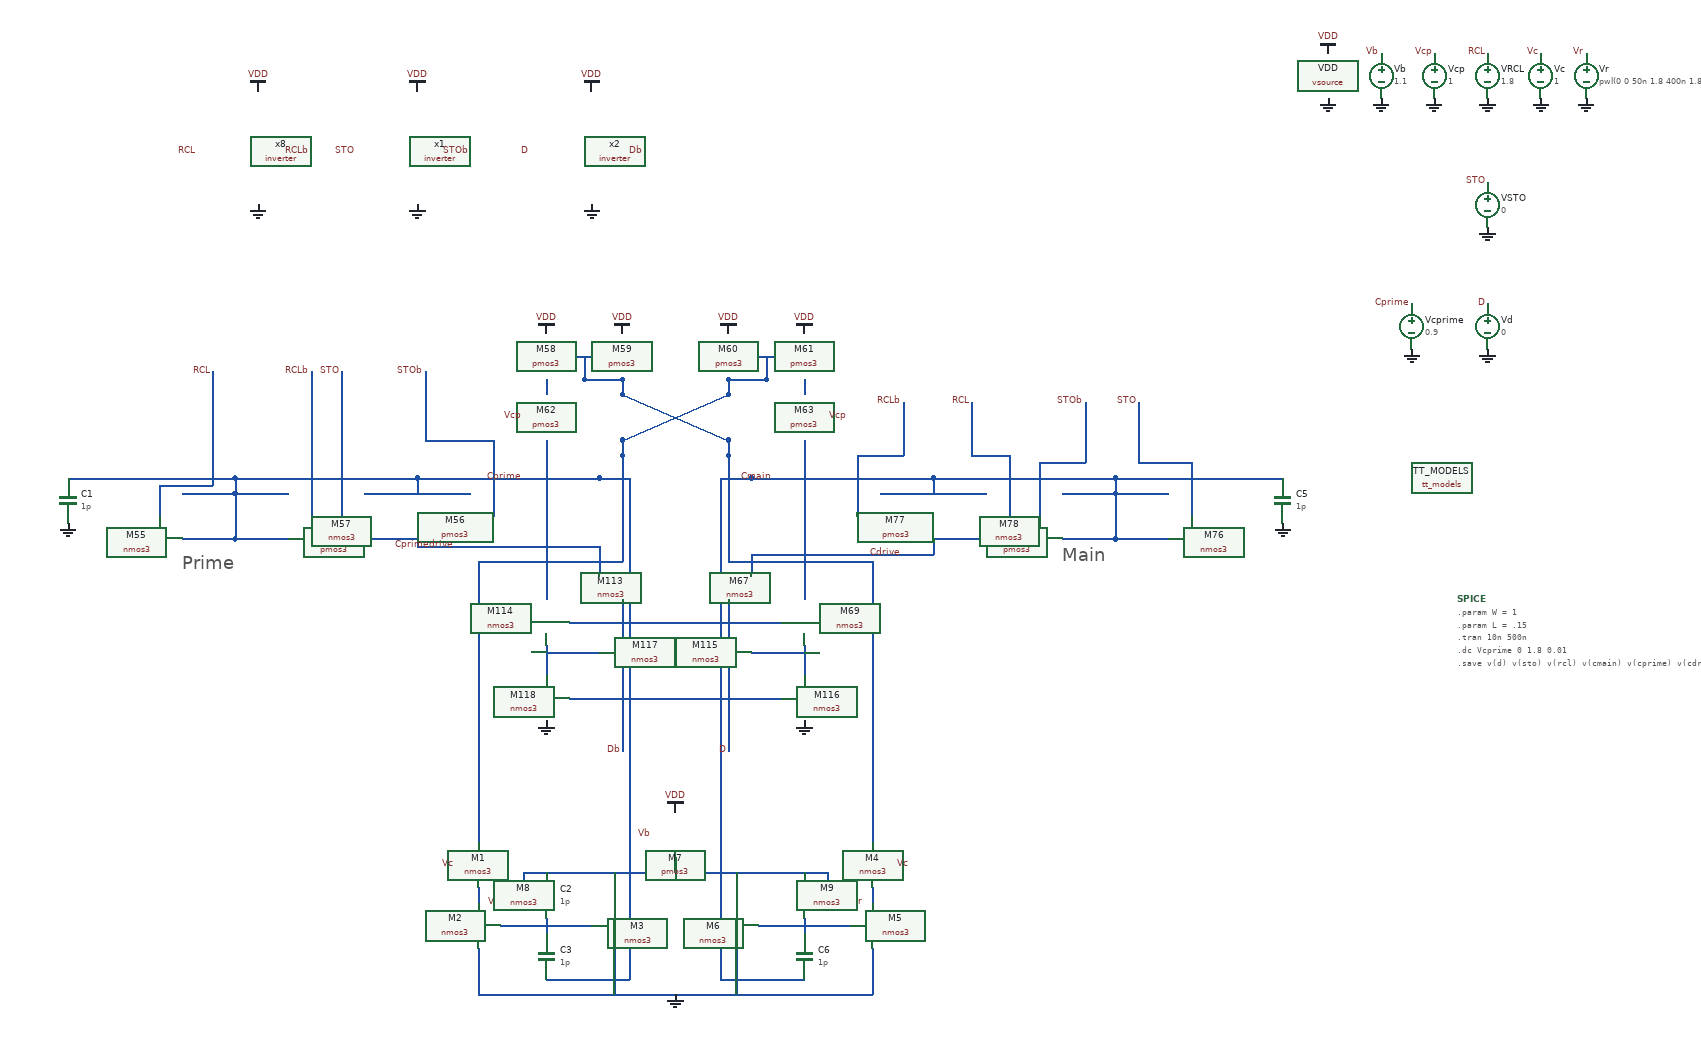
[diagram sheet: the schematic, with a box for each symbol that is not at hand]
v {xschem version=3.4.3 file_version=1.2
}
G {}
K {}
V {}
S {}
E {}
T {Prime} -550 -80 0 0 0.7 0.7 {}
T {Main} 610 -90 0 0 0.7 0.7 {}
N -550 -160 -410 -160 {
lab=Cprime}
N -480 -180 -480 -160 {
lab=Cprime}
N -310 -160 -170 -160 {
lab=Cprime}
N -480 -180 -240 -180 {
lab=Cprime}
N -240 -180 -240 -160 {
lab=Cprime}
N -310 -100 -170 -100 {
lab=Cprimedrive}
N -40 -340 0 -340 {
lab=#net1}
N -20 -340 -20 -310 {
lab=#net1}
N -20 -310 30 -310 {
lab=#net1}
N 200 -340 240 -340 {
lab=#net2}
N 220 -340 220 -310 {
lab=#net2}
N 170 -310 220 -310 {
lab=#net2}
N 30 -310 30 -290 {
lab=#net1}
N 170 -230 170 -210 {
lab=#net1}
N 170 -310 170 -290 {
lab=#net2}
N 30 -230 30 -210 {
lab=#net2}
N 30 -230 170 -290 {
lab=#net2}
N 30 -290 170 -230 {
lab=#net1}
N 270 -310 270 -290 {
lab=#net3}
N -70 -310 -70 -290 {
lab=#net4}
N -240 -180 0 -180 {
lab=Cprime}
N -70 -230 -70 -20 {
lab=Cprimedrive}
N 270 -230 270 -20 {
lab=Cdrive}
N 610 -160 750 -160 {
lab=Cmain}
N 680 -180 680 -160 {
lab=Cmain}
N 370 -160 510 -160 {
lab=Cmain}
N 440 -180 680 -180 {
lab=Cmain}
N 440 -180 440 -160 {
lab=Cmain}
N 370 -100 510 -100 {
lab=Cdrive}
N 200 -180 440 -180 {
lab=Cmain}
N -550 -160 -410 -160 {
lab=Cprime}
N -480 -180 -480 -160 {
lab=Cprime}
N -310 -160 -170 -160 {
lab=Cprime}
N -480 -180 -240 -180 {
lab=Cprime}
N -240 -180 -240 -160 {
lab=Cprime}
N -310 -100 -170 -100 {
lab=Cprimedrive}
N -40 -340 0 -340 {
lab=#net1}
N -20 -340 -20 -310 {
lab=#net1}
N -20 -310 30 -310 {
lab=#net1}
N 200 -340 240 -340 {
lab=#net2}
N 220 -340 220 -310 {
lab=#net2}
N 170 -310 220 -310 {
lab=#net2}
N 30 -310 30 -290 {
lab=#net1}
N 170 -230 170 -210 {
lab=#net1}
N 170 -310 170 -290 {
lab=#net2}
N 30 -230 30 -210 {
lab=#net2}
N 30 -230 170 -290 {
lab=#net2}
N 30 -290 170 -230 {
lab=#net1}
N 270 -310 270 -290 {
lab=#net3}
N -70 -310 -70 -290 {
lab=#net4}
N -240 -180 0 -180 {
lab=Cprime}
N -70 -230 -70 -20 {
lab=Cprimedrive}
N 270 -230 270 -20 {
lab=Cdrive}
N 610 -160 750 -160 {
lab=Cmain}
N 680 -180 680 -160 {
lab=Cmain}
N 370 -160 510 -160 {
lab=Cmain}
N 440 -180 680 -180 {
lab=Cmain}
N 440 -180 440 -160 {
lab=Cmain}
N 370 -100 510 -100 {
lab=Cdrive}
N 200 -180 440 -180 {
lab=Cmain}
N -480 -160 -480 -100 {
lab=Cprime}
N -480 -100 -410 -100 {
lab=Cprime}
N -550 -100 -480 -100 {
lab=Cprime}
N -580 -170 -580 -130 {
lab=RCL}
N -580 -170 -510 -170 {
lab=RCL}
N -510 -320 -510 -170 {
lab=RCL}
N -380 -320 -380 -130 {
lab=RCLb}
N -340 -320 -340 -130 {
lab=STO}
N -140 -230 -140 -130 {
lab=STOb}
N -230 -230 -140 -230 {
lab=STOb}
N -230 -320 -230 -230 {
lab=STOb}
N -240 -100 -240 -90 {
lab=Cprimedrive}
N 0 -90 0 -50 {
lab=Cprimedrive}
N 680 -160 680 -100 {
lab=Cmain}
N 610 -100 680 -100 {
lab=Cmain}
N 680 -100 750 -100 {
lab=Cmain}
N 640 -280 640 -200 {
lab=STOb}
N 580 -200 640 -200 {
lab=STOb}
N 580 -200 580 -130 {
lab=STOb}
N 710 -280 710 -200 {
lab=STO}
N 710 -200 780 -200 {
lab=STO}
N 780 -200 780 -130 {
lab=STO}
N 400 -280 400 -210 {
lab=RCLb}
N 340 -210 400 -210 {
lab=RCLb}
N 340 -210 340 -130 {
lab=RCLb}
N 200 -80 200 -50 {
lab=Cdrive}
N 440 -100 440 -80 {
lab=Cdrive}
N 490 -280 490 -210 {
lab=RCL}
N 490 -210 540 -210 {
lab=RCL}
N 540 -210 540 -130 {
lab=RCL}
N -240 -90 -70 -90 {
lab=Cprimedrive}
N -70 -90 0 -90 {
lab=Cprimedrive}
N 200 -80 270 -80 {
lab=Cdrive}
N 270 -80 440 -80 {
lab=Cdrive}
N -40 10 240 10 {
lab=#net5}
N 270 40 270 80 {
lab=#net6}
N 200 50 270 50 {
lab=#net6}
N -70 40 -70 80 {
lab=#net7}
N -70 50 0 50 {
lab=#net7}
N 30 -20 30 180 {
lab=Db}
N 170 -20 170 180 {
lab=D}
N -40 110 240 110 {
lab=#net8}
N 680 -180 900 -180 {
lab=Cmain}
N -700 -180 -480 -180 {
lab=Cprime}
N -160 360 -160 380 {
lab=#net9}
N -130 410 -10 410 {
lab=#net10}
N -70 410 -70 420 {
lab=#net10}
N -70 400 -70 410 {
lab=#net10}
N 210 410 330 410 {
lab=#net11}
N 270 400 270 410 {
lab=#net11}
N 270 410 270 420 {
lab=#net11}
N -160 440 -160 500 {
lab=GND}
N -160 500 360 500 {
lab=GND}
N 360 440 360 500 {
lab=GND}
N 20 440 20 500 {
lab=GND}
N 180 440 180 500 {
lab=GND}
N -70 340 270 340 {
lab=#net12}
N 180 340 180 380 {
lab=#net12}
N 20 340 20 380 {
lab=#net12}
N 100 320 100 340 {
lab=#net12}
N 360 360 360 380 {
lab=#net13}
N 0 -180 40 -180 {
lab=Cprime}
N 40 -180 40 480 {
lab=Cprime}
N -70 480 40 480 {
lab=Cprime}
N 160 -180 200 -180 {
lab=Cmain}
N 160 -180 160 480 {
lab=Cmain}
N 160 480 270 480 {
lab=Cmain}
N -160 -70 -160 300 {
lab=#net2}
N -160 -70 30 -70 {
lab=#net2}
N 30 -210 30 -70 {
lab=#net2}
N 360 -70 360 300 {
lab=#net1}
N 170 -70 360 -70 {
lab=#net1}
N 170 -210 170 -70 {
lab=#net1}
N -100 340 -100 350 {
lab=#net12}
N -100 340 -70 340 {
lab=#net12}
N 300 340 300 350 {
lab=#net12}
N 270 340 300 340 {
lab=#net12}
C {madvlsi/pmos3.sym} -410 -130 0 1 {name=M54
L=\{L\}
W=\{W\}
body=VDD
nf=1
mult=1
ad="'int((nf+1)/2) * W/nf * 0.29'" 
pd="'2*int((nf+1)/2) * (W/nf + 0.29)'"
as="'int((nf+2)/2) * W/nf * 0.29'" 
ps="'2*int((nf+2)/2) * (W/nf + 0.29)'"
nrd="'0.29 / W'" nrs="'0.29 / W'"
sa=0 sb=0 sd=0
model=pfet_01v8
spiceprefix=X
}
C {madvlsi/nmos3.sym} -550 -130 2 1 {name=M55
L=\{L\}
W=\{W\}
body=GND
nf=1
mult=1
ad="'int((nf+1)/2) * W/nf * 0.29'" 
pd="'2*int((nf+1)/2) * (W/nf + 0.29)'"
as="'int((nf+2)/2) * W/nf * 0.29'" 
ps="'2*int((nf+2)/2) * (W/nf + 0.29)'"
nrd="'0.29 / W'" nrs="'0.29 / W'"
sa=0 sb=0 sd=0
model=nfet_01v8
spiceprefix=X
}
C {madvlsi/pmos3.sym} -170 -130 0 1 {name=M56
L=\{L\}
W=\{W\}
body=VDD
nf=1
mult=1
ad="'int((nf+1)/2) * W/nf * 0.29'" 
pd="'2*int((nf+1)/2) * (W/nf + 0.29)'"
as="'int((nf+2)/2) * W/nf * 0.29'" 
ps="'2*int((nf+2)/2) * (W/nf + 0.29)'"
nrd="'0.29 / W'" nrs="'0.29 / W'"
sa=0 sb=0 sd=0
model=pfet_01v8
spiceprefix=X
}
C {madvlsi/nmos3.sym} -310 -130 2 1 {name=M57
L=\{L\}
W=\{W\}
body=GND
nf=1
mult=1
ad="'int((nf+1)/2) * W/nf * 0.29'" 
pd="'2*int((nf+1)/2) * (W/nf + 0.29)'"
as="'int((nf+2)/2) * W/nf * 0.29'" 
ps="'2*int((nf+2)/2) * (W/nf + 0.29)'"
nrd="'0.29 / W'" nrs="'0.29 / W'"
sa=0 sb=0 sd=0
model=nfet_01v8
spiceprefix=X
}
C {madvlsi/pmos3.sym} -70 -340 0 1 {name=M58
L=\{L\}
W=\{W\}
body=VDD
nf=1
mult=1
ad="'int((nf+1)/2) * W/nf * 0.29'" 
pd="'2*int((nf+1)/2) * (W/nf + 0.29)'"
as="'int((nf+2)/2) * W/nf * 0.29'" 
ps="'2*int((nf+2)/2) * (W/nf + 0.29)'"
nrd="'0.29 / W'" nrs="'0.29 / W'"
sa=0 sb=0 sd=0
model=pfet_01v8
spiceprefix=X
}
C {madvlsi/pmos3.sym} 30 -340 0 0 {name=M59
L=\{L\}
W=\{W\}
body=VDD
nf=1
mult=1
ad="'int((nf+1)/2) * W/nf * 0.29'" 
pd="'2*int((nf+1)/2) * (W/nf + 0.29)'"
as="'int((nf+2)/2) * W/nf * 0.29'" 
ps="'2*int((nf+2)/2) * (W/nf + 0.29)'"
nrd="'0.29 / W'" nrs="'0.29 / W'"
sa=0 sb=0 sd=0
model=pfet_01v8
spiceprefix=X
}
C {madvlsi/pmos3.sym} 170 -340 0 1 {name=M60
L=\{L\}
W=\{W\}
body=VDD
nf=1
mult=1
ad="'int((nf+1)/2) * W/nf * 0.29'" 
pd="'2*int((nf+1)/2) * (W/nf + 0.29)'"
as="'int((nf+2)/2) * W/nf * 0.29'" 
ps="'2*int((nf+2)/2) * (W/nf + 0.29)'"
nrd="'0.29 / W'" nrs="'0.29 / W'"
sa=0 sb=0 sd=0
model=pfet_01v8
spiceprefix=X
}
C {madvlsi/pmos3.sym} 270 -340 0 0 {name=M61
L=\{L\}
W=\{W\}
body=VDD
nf=1
mult=1
ad="'int((nf+1)/2) * W/nf * 0.29'" 
pd="'2*int((nf+1)/2) * (W/nf + 0.29)'"
as="'int((nf+2)/2) * W/nf * 0.29'" 
ps="'2*int((nf+2)/2) * (W/nf + 0.29)'"
nrd="'0.29 / W'" nrs="'0.29 / W'"
sa=0 sb=0 sd=0
model=pfet_01v8
spiceprefix=X
}
C {madvlsi/pmos3.sym} -70 -260 0 0 {name=M62
L=\{L\}
W=\{W\}
body=VDD
nf=1
mult=1
ad="'int((nf+1)/2) * W/nf * 0.29'" 
pd="'2*int((nf+1)/2) * (W/nf + 0.29)'"
as="'int((nf+2)/2) * W/nf * 0.29'" 
ps="'2*int((nf+2)/2) * (W/nf + 0.29)'"
nrd="'0.29 / W'" nrs="'0.29 / W'"
sa=0 sb=0 sd=0
model=pfet_01v8
spiceprefix=X
}
C {madvlsi/pmos3.sym} 270 -260 0 1 {name=M63
L=\{L\}
W=\{W\}
body=VDD
nf=1
mult=1
ad="'int((nf+1)/2) * W/nf * 0.29'" 
pd="'2*int((nf+1)/2) * (W/nf + 0.29)'"
as="'int((nf+2)/2) * W/nf * 0.29'" 
ps="'2*int((nf+2)/2) * (W/nf + 0.29)'"
nrd="'0.29 / W'" nrs="'0.29 / W'"
sa=0 sb=0 sd=0
model=pfet_01v8
spiceprefix=X
}
C {madvlsi/pmos3.sym} 610 -130 0 0 {name=M75
L=\{L\}
W=\{W\}
body=VDD
nf=1
mult=1
ad="'int((nf+1)/2) * W/nf * 0.29'" 
pd="'2*int((nf+1)/2) * (W/nf + 0.29)'"
as="'int((nf+2)/2) * W/nf * 0.29'" 
ps="'2*int((nf+2)/2) * (W/nf + 0.29)'"
nrd="'0.29 / W'" nrs="'0.29 / W'"
sa=0 sb=0 sd=0
model=pfet_01v8
spiceprefix=X
}
C {madvlsi/nmos3.sym} 750 -130 2 0 {name=M76
L=\{L\}
W=\{W\}
body=GND
nf=1
mult=1
ad="'int((nf+1)/2) * W/nf * 0.29'" 
pd="'2*int((nf+1)/2) * (W/nf + 0.29)'"
as="'int((nf+2)/2) * W/nf * 0.29'" 
ps="'2*int((nf+2)/2) * (W/nf + 0.29)'"
nrd="'0.29 / W'" nrs="'0.29 / W'"
sa=0 sb=0 sd=0
model=nfet_01v8
spiceprefix=X
}
C {madvlsi/pmos3.sym} 370 -130 0 0 {name=M77
L=\{L\}
W=\{W\}
body=VDD
nf=1
mult=1
ad="'int((nf+1)/2) * W/nf * 0.29'" 
pd="'2*int((nf+1)/2) * (W/nf + 0.29)'"
as="'int((nf+2)/2) * W/nf * 0.29'" 
ps="'2*int((nf+2)/2) * (W/nf + 0.29)'"
nrd="'0.29 / W'" nrs="'0.29 / W'"
sa=0 sb=0 sd=0
model=pfet_01v8
spiceprefix=X
}
C {madvlsi/nmos3.sym} 510 -130 2 0 {name=M78
L=\{L\}
W=\{W\}
body=GND
nf=1
mult=1
ad="'int((nf+1)/2) * W/nf * 0.29'" 
pd="'2*int((nf+1)/2) * (W/nf + 0.29)'"
as="'int((nf+2)/2) * W/nf * 0.29'" 
ps="'2*int((nf+2)/2) * (W/nf + 0.29)'"
nrd="'0.29 / W'" nrs="'0.29 / W'"
sa=0 sb=0 sd=0
model=nfet_01v8
spiceprefix=X
}
C {devices/lab_pin.sym} -100 -260 0 0 {name=p78 sig_type=std_logic lab=Vcp}
C {devices/lab_pin.sym} 640 -280 1 0 {name=p91 sig_type=std_logic lab=STOb}
C {devices/lab_pin.sym} -230 -320 1 0 {name=p48 sig_type=std_logic lab=STOb}
C {devices/lab_pin.sym} 400 -280 1 0 {name=p70 sig_type=std_logic lab=RCLb}
C {devices/lab_pin.sym} -380 -320 1 0 {name=p46 sig_type=std_logic lab=RCLb}
C {devices/lab_pin.sym} -340 -320 1 0 {name=p29 sig_type=std_logic lab=STO}
C {devices/lab_pin.sym} 710 -280 1 0 {name=p30 sig_type=std_logic lab=STO}
C {devices/lab_pin.sym} -510 -320 1 0 {name=p45 sig_type=std_logic lab=RCL}
C {devices/lab_pin.sym} 490 -280 1 0 {name=p53 sig_type=std_logic lab=RCL}
C {devices/lab_pin.sym} -100 -180 3 0 {name=p59 sig_type=std_logic lab=Cprime}
C {devices/lab_pin.sym} 300 -260 2 0 {name=p8 sig_type=std_logic lab=Vcp}
C {madvlsi/vdd.sym} -70 -370 0 0 {name=l54 lab=VDD}
C {madvlsi/vdd.sym} 30 -370 0 0 {name=l55 lab=VDD}
C {madvlsi/vdd.sym} 170 -370 0 0 {name=l56 lab=VDD}
C {madvlsi/vdd.sym} 270 -370 0 0 {name=l57 lab=VDD}
C {devices/lab_pin.sym} -190 -90 3 0 {name=p2 sig_type=std_logic lab=Cprimedrive}
C {devices/lab_pin.sym} 400 -80 3 0 {name=p11 sig_type=std_logic lab=Cdrive}
C {madvlsi/nmos3.sym} 200 -20 0 0 {name=M67
L=\{L\}
W=\{W\}
body=GND
nf=1
mult=1
ad="'int((nf+1)/2) * W/nf * 0.29'" 
pd="'2*int((nf+1)/2) * (W/nf + 0.29)'"
as="'int((nf+2)/2) * W/nf * 0.29'" 
ps="'2*int((nf+2)/2) * (W/nf + 0.29)'"
nrd="'0.29 / W'" nrs="'0.29 / W'"
sa=0 sb=0 sd=0
model=nfet_01v8
spiceprefix=X
}
C {madvlsi/nmos3.sym} 270 10 0 0 {name=M69
L=\{L\}
W=\{W\}
body=GND
nf=1
mult=1
ad="'int((nf+1)/2) * W/nf * 0.29'" 
pd="'2*int((nf+1)/2) * (W/nf + 0.29)'"
as="'int((nf+2)/2) * W/nf * 0.29'" 
ps="'2*int((nf+2)/2) * (W/nf + 0.29)'"
nrd="'0.29 / W'" nrs="'0.29 / W'"
sa=0 sb=0 sd=0
model=nfet_01v8
spiceprefix=X
}
C {madvlsi/nmos3.sym} 0 -20 0 1 {name=M113
L=\{L\}
W=\{W\}
body=GND
nf=1
mult=1
ad="'int((nf+1)/2) * W/nf * 0.29'" 
pd="'2*int((nf+1)/2) * (W/nf + 0.29)'"
as="'int((nf+2)/2) * W/nf * 0.29'" 
ps="'2*int((nf+2)/2) * (W/nf + 0.29)'"
nrd="'0.29 / W'" nrs="'0.29 / W'"
sa=0 sb=0 sd=0
model=nfet_01v8
spiceprefix=X
}
C {madvlsi/nmos3.sym} -70 10 0 1 {name=M114
L=\{L\}
W=\{W\}
body=GND
nf=1
mult=1
ad="'int((nf+1)/2) * W/nf * 0.29'" 
pd="'2*int((nf+1)/2) * (W/nf + 0.29)'"
as="'int((nf+2)/2) * W/nf * 0.29'" 
ps="'2*int((nf+2)/2) * (W/nf + 0.29)'"
nrd="'0.29 / W'" nrs="'0.29 / W'"
sa=0 sb=0 sd=0
model=nfet_01v8
spiceprefix=X
}
C {madvlsi/nmos3.sym} 200 80 0 0 {name=M115
L=\{L\}
W=\{W\}
body=GND
nf=1
mult=1
ad="'int((nf+1)/2) * W/nf * 0.29'" 
pd="'2*int((nf+1)/2) * (W/nf + 0.29)'"
as="'int((nf+2)/2) * W/nf * 0.29'" 
ps="'2*int((nf+2)/2) * (W/nf + 0.29)'"
nrd="'0.29 / W'" nrs="'0.29 / W'"
sa=0 sb=0 sd=0
model=nfet_01v8
spiceprefix=X
}
C {madvlsi/nmos3.sym} 270 110 0 0 {name=M116
L=\{L\}
W=\{W\}
body=GND
nf=1
mult=1
ad="'int((nf+1)/2) * W/nf * 0.29'" 
pd="'2*int((nf+1)/2) * (W/nf + 0.29)'"
as="'int((nf+2)/2) * W/nf * 0.29'" 
ps="'2*int((nf+2)/2) * (W/nf + 0.29)'"
nrd="'0.29 / W'" nrs="'0.29 / W'"
sa=0 sb=0 sd=0
model=nfet_01v8
spiceprefix=X
}
C {madvlsi/nmos3.sym} 0 80 0 1 {name=M117
L=\{L\}
W=\{W\}
body=GND
nf=1
mult=1
ad="'int((nf+1)/2) * W/nf * 0.29'" 
pd="'2*int((nf+1)/2) * (W/nf + 0.29)'"
as="'int((nf+2)/2) * W/nf * 0.29'" 
ps="'2*int((nf+2)/2) * (W/nf + 0.29)'"
nrd="'0.29 / W'" nrs="'0.29 / W'"
sa=0 sb=0 sd=0
model=nfet_01v8
spiceprefix=X
}
C {madvlsi/nmos3.sym} -70 110 0 1 {name=M118
L=\{L\}
W=\{W\}
body=GND
nf=1
mult=1
ad="'int((nf+1)/2) * W/nf * 0.29'" 
pd="'2*int((nf+1)/2) * (W/nf + 0.29)'"
as="'int((nf+2)/2) * W/nf * 0.29'" 
ps="'2*int((nf+2)/2) * (W/nf + 0.29)'"
nrd="'0.29 / W'" nrs="'0.29 / W'"
sa=0 sb=0 sd=0
model=nfet_01v8
spiceprefix=X
}
C {devices/lab_pin.sym} 30 180 3 0 {name=p39 sig_type=std_logic lab=Db}
C {devices/lab_pin.sym} 170 180 3 0 {name=p40 sig_type=std_logic lab=D}
C {madvlsi/gnd.sym} 270 140 0 0 {name=l67 lab=GND}
C {madvlsi/gnd.sym} -70 140 0 0 {name=l68 lab=GND}
C {devices/lab_pin.sym} 230 -180 3 0 {name=p1 sig_type=std_logic lab=Cmain}
C {./inverter.sym} -420 -610 0 0 {name=x8}
C {devices/lab_pin.sym} -530 -610 1 0 {name=p3 sig_type=std_logic lab=RCL}
C {devices/lab_pin.sym} -380 -610 1 0 {name=p4 sig_type=std_logic lab=RCLb}
C {madvlsi/vdd.sym} -450 -690 0 0 {name=l1 lab=VDD}
C {madvlsi/gnd.sym} -450 -540 0 0 {name=l2 lab=GND}
C {./inverter.sym} -210 -610 0 0 {name=x1}
C {madvlsi/vdd.sym} -240 -690 0 0 {name=l3 lab=VDD}
C {madvlsi/gnd.sym} -240 -540 0 0 {name=l4 lab=GND}
C {devices/lab_pin.sym} -320 -610 1 0 {name=p5 sig_type=std_logic lab=STO}
C {devices/lab_pin.sym} -170 -610 1 0 {name=p6 sig_type=std_logic lab=STOb}
C {./inverter.sym} 20 -610 0 0 {name=x2}
C {madvlsi/gnd.sym} -10 -540 0 0 {name=l5 lab=GND}
C {madvlsi/vdd.sym} -10 -690 0 0 {name=l6 lab=VDD}
C {devices/lab_pin.sym} -90 -610 3 0 {name=p7 sig_type=std_logic lab=D}
C {devices/lab_pin.sym} 60 -610 3 0 {name=p9 sig_type=std_logic lab=Db}
C {madvlsi/vsource.sym} 960 -710 0 0 {name=VDD
value=1.8}
C {madvlsi/vdd.sym} 960 -740 0 0 {name=l7 lab=VDD}
C {madvlsi/gnd.sym} 960 -680 0 0 {name=l8 lab=GND}
C {madvlsi/vsource.sym} 1030 -710 0 0 {name=Vb
value=1.1}
C {madvlsi/gnd.sym} 1030 -680 0 0 {name=l10 lab=GND}
C {devices/lab_pin.sym} 1030 -740 1 0 {name=p98 sig_type=std_logic lab=Vb}
C {madvlsi/vsource.sym} 1100 -710 0 0 {name=Vcp
value=1}
C {madvlsi/gnd.sym} 1100 -680 0 0 {name=l11 lab=GND}
C {devices/lab_pin.sym} 1100 -740 1 0 {name=p99 sig_type=std_logic lab=Vcp}
C {madvlsi/gnd.sym} 1170 -680 0 0 {name=l18 lab=GND}
C {devices/lab_pin.sym} 1170 -740 1 0 {name=p106 sig_type=std_logic lab=RCL}
C {madvlsi/vsource.sym} 1170 -710 0 0 {name=VRCL
value=1.8}
C {madvlsi/vsource.sym} 1170 -380 0 0 {name=Vd
value=0}
C {madvlsi/gnd.sym} 1170 -350 0 0 {name=l23 lab=GND}
C {devices/lab_pin.sym} 1170 -410 1 0 {name=p69 sig_type=std_logic lab=D}
C {madvlsi/capacitor.sym} 900 -150 0 0 {name=C5
value=1p
m=1}
C {madvlsi/gnd.sym} 900 -120 0 0 {name=l78 lab=GND}
C {madvlsi/capacitor.sym} -700 -150 0 0 {name=C1
value=1p
m=1}
C {madvlsi/gnd.sym} -700 -120 0 0 {name=l9 lab=GND}
C {madvlsi/gnd.sym} 1170 -510 0 0 {name=l12 lab=GND}
C {devices/lab_pin.sym} 1170 -570 1 0 {name=p10 sig_type=std_logic lab=STO}
C {madvlsi/vsource.sym} 1170 -540 0 0 {name=VSTO
value=0}
C {devices/code_shown.sym} 1130 -20 0 0 {name=SPICE only_toplevel=false value=".param W = 1
.param L = .15
.tran 10n 500n
.dc Vcprime 0 1.8 0.01
.save v(d) v(sto) v(rcl) v(cmain) v(cprime) v(cdrive) v(cprimedrive)"
}
C {madvlsi/tt_models.sym} 1110 -180 0 0 {
name=TT_MODELS
only_toplevel=false
value=".option wnflag=1
.param MC_SWITCH=0.0
.lib ~/skywater/skywater-pdk/libraries/sky130_fd_pr_ngspice/latest/models/sky130.lib.spice tt"
}
C {devices/lab_pin.sym} 1070 -410 1 0 {name=p12 sig_type=std_logic lab=Cprime}
C {madvlsi/vsource.sym} 1070 -380 0 0 {name=Vcprime
value=0.9}
C {madvlsi/gnd.sym} 1070 -350 0 0 {name=l13 lab=GND}
C {madvlsi/nmos3.sym} -160 330 0 0 {name=M1
L=\{L\}
W=\{W\}
body=GND
nf=1
mult=1
ad="'int((nf+1)/2) * W/nf * 0.29'" 
pd="'2*int((nf+1)/2) * (W/nf + 0.29)'"
as="'int((nf+2)/2) * W/nf * 0.29'" 
ps="'2*int((nf+2)/2) * (W/nf + 0.29)'"
nrd="'0.29 / W'" nrs="'0.29 / W'"
sa=0 sb=0 sd=0
model=nfet_01v8
spiceprefix=X
}
C {madvlsi/nmos3.sym} -160 410 0 1 {name=M2
L=\{L\}
W=\{W\}
body=GND
nf=1
mult=1
ad="'int((nf+1)/2) * W/nf * 0.29'" 
pd="'2*int((nf+1)/2) * (W/nf + 0.29)'"
as="'int((nf+2)/2) * W/nf * 0.29'" 
ps="'2*int((nf+2)/2) * (W/nf + 0.29)'"
nrd="'0.29 / W'" nrs="'0.29 / W'"
sa=0 sb=0 sd=0
model=nfet_01v8
spiceprefix=X
}
C {madvlsi/capacitor.sym} -70 370 0 0 {name=C2
value=1p
m=1}
C {madvlsi/capacitor.sym} -70 450 0 0 {name=C3
value=1p
m=1}
C {madvlsi/nmos3.sym} 20 410 0 0 {name=M3
L=\{L\}
W=\{W\}
body=GND
nf=1
mult=1
ad="'int((nf+1)/2) * W/nf * 0.29'" 
pd="'2*int((nf+1)/2) * (W/nf + 0.29)'"
as="'int((nf+2)/2) * W/nf * 0.29'" 
ps="'2*int((nf+2)/2) * (W/nf + 0.29)'"
nrd="'0.29 / W'" nrs="'0.29 / W'"
sa=0 sb=0 sd=0
model=nfet_01v8
spiceprefix=X
}
C {madvlsi/nmos3.sym} 360 330 0 1 {name=M4
L=\{L\}
W=\{W\}
body=GND
nf=1
mult=1
ad="'int((nf+1)/2) * W/nf * 0.29'" 
pd="'2*int((nf+1)/2) * (W/nf + 0.29)'"
as="'int((nf+2)/2) * W/nf * 0.29'" 
ps="'2*int((nf+2)/2) * (W/nf + 0.29)'"
nrd="'0.29 / W'" nrs="'0.29 / W'"
sa=0 sb=0 sd=0
model=nfet_01v8
spiceprefix=X
}
C {madvlsi/nmos3.sym} 360 410 0 0 {name=M5
L=\{L\}
W=\{W\}
body=GND
nf=1
mult=1
ad="'int((nf+1)/2) * W/nf * 0.29'" 
pd="'2*int((nf+1)/2) * (W/nf + 0.29)'"
as="'int((nf+2)/2) * W/nf * 0.29'" 
ps="'2*int((nf+2)/2) * (W/nf + 0.29)'"
nrd="'0.29 / W'" nrs="'0.29 / W'"
sa=0 sb=0 sd=0
model=nfet_01v8
spiceprefix=X
}
C {madvlsi/capacitor.sym} 270 370 0 1 {name=C4
value=1p
m=1}
C {madvlsi/capacitor.sym} 270 450 0 1 {name=C6
value=1p
m=1}
C {madvlsi/nmos3.sym} 180 410 0 1 {name=M6
L=\{L\}
W=\{W\}
body=GND
nf=1
mult=1
ad="'int((nf+1)/2) * W/nf * 0.29'" 
pd="'2*int((nf+1)/2) * (W/nf + 0.29)'"
as="'int((nf+2)/2) * W/nf * 0.29'" 
ps="'2*int((nf+2)/2) * (W/nf + 0.29)'"
nrd="'0.29 / W'" nrs="'0.29 / W'"
sa=0 sb=0 sd=0
model=nfet_01v8
spiceprefix=X
}
C {madvlsi/gnd.sym} 100 500 0 0 {name=l14 lab=GND}
C {madvlsi/pmos3.sym} 100 290 0 0 {name=M7
L=\{L\}
W=\{W\}
body=VDD
nf=1
mult=1
ad="'int((nf+1)/2) * W/nf * 0.29'" 
pd="'2*int((nf+1)/2) * (W/nf + 0.29)'"
as="'int((nf+2)/2) * W/nf * 0.29'" 
ps="'2*int((nf+2)/2) * (W/nf + 0.29)'"
nrd="'0.29 / W'" nrs="'0.29 / W'"
sa=0 sb=0 sd=0
model=pfet_01v8
spiceprefix=X
}
C {madvlsi/vdd.sym} 100 260 0 0 {name=l15 lab=VDD}
C {devices/lab_pin.sym} 70 290 0 0 {name=p13 sig_type=std_logic lab=Vb}
C {devices/lab_pin.sym} -190 330 0 0 {name=p14 sig_type=std_logic lab=Vc}
C {devices/lab_pin.sym} 390 330 0 1 {name=p15 sig_type=std_logic lab=Vc}
C {devices/lab_pin.sym} -130 380 0 0 {name=p16 sig_type=std_logic lab=Vr}
C {devices/lab_pin.sym} 330 380 0 1 {name=p17 sig_type=std_logic lab=Vr}
C {madvlsi/vsource.sym} 1240 -710 0 0 {name=Vc
value=1}
C {madvlsi/gnd.sym} 1240 -680 0 0 {name=l16 lab=GND}
C {devices/lab_pin.sym} 1240 -740 1 0 {name=p18 sig_type=std_logic lab=Vc}
C {madvlsi/vsource.sym} 1300 -710 0 0 {name=Vr
value="pwl(0 0 50n 1.8 400n 1.8 500n 0)"}
C {madvlsi/gnd.sym} 1300 -680 0 0 {name=l17 lab=GND}
C {devices/lab_pin.sym} 1300 -740 1 0 {name=p19 sig_type=std_logic lab=Vr}
C {madvlsi/nmos3.sym} -100 380 0 0 {name=M8
L=\{L\}
W=\{W\}
body=GND
nf=1
mult=1
ad="'int((nf+1)/2) * W/nf * 0.29'" 
pd="'2*int((nf+1)/2) * (W/nf + 0.29)'"
as="'int((nf+2)/2) * W/nf * 0.29'" 
ps="'2*int((nf+2)/2) * (W/nf + 0.29)'"
nrd="'0.29 / W'" nrs="'0.29 / W'"
sa=0 sb=0 sd=0
model=nfet_01v8
spiceprefix=X
}
C {madvlsi/nmos3.sym} 300 380 0 1 {name=M9
L=\{L\}
W=\{W\}
body=GND
nf=1
mult=1
ad="'int((nf+1)/2) * W/nf * 0.29'" 
pd="'2*int((nf+1)/2) * (W/nf + 0.29)'"
as="'int((nf+2)/2) * W/nf * 0.29'" 
ps="'2*int((nf+2)/2) * (W/nf + 0.29)'"
nrd="'0.29 / W'" nrs="'0.29 / W'"
sa=0 sb=0 sd=0
model=nfet_01v8
spiceprefix=X
}
